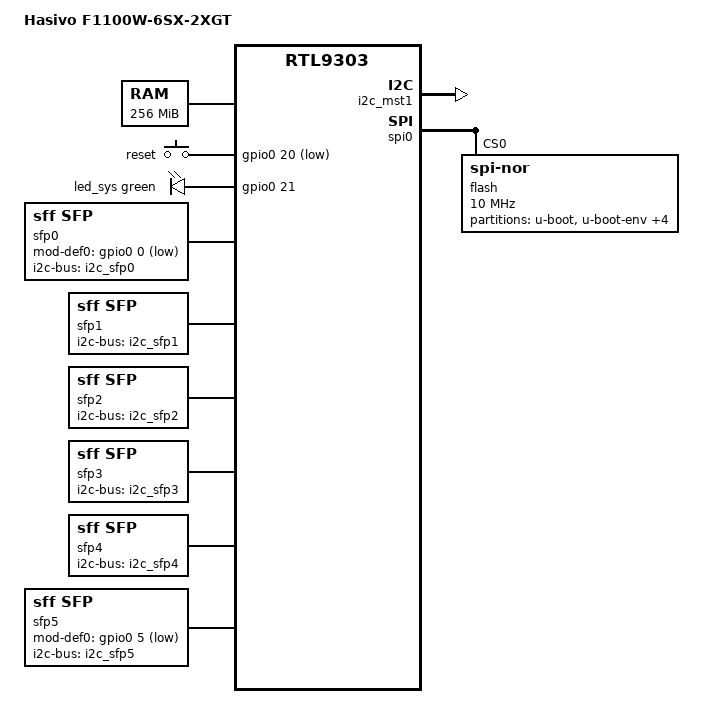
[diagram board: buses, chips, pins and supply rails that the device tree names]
// SPDX-License-Identifier: GPL-2.0-or-later
/dts-v1/;

#include "rtl930x.dtsi"

#include <dt-bindings/input/input.h>
#include <dt-bindings/gpio/gpio.h>
#include <dt-bindings/leds/common.h>

/ {
	compatible = "hasivo,f1100w-6sx-2xgt", "realtek,rtl9303-soc";
	model = "Hasivo F1100W-6SX-2XGT";

	memory@0 {
		reg = <0x00000000 0x10000000>;
	};

	aliases {
		led-boot = &led_sys;
		led-failsafe = &led_sys;
		led-running = &led_sys;
		led-upgrade = &led_sys;

		i2c0 = &i2c_sfp0;
		i2c1 = &i2c_sfp1;
		i2c2 = &i2c_sfp2;
		i2c3 = &i2c_sfp3;
		i2c4 = &i2c_sfp4;
		i2c5 = &i2c_sfp5;
	};

	chosen {
		stdout-path = "serial0:38400n8";
	};

	keys {
		compatible = "gpio-keys";

		button-reset {
			label = "reset";
			gpios = <&gpio0 20 GPIO_ACTIVE_LOW>;
			linux,code = <KEY_RESTART>;
		};
	};

	leds {
		compatible = "gpio-leds";

		/* GPIO confirmed; polarity provisionally follows the related 4SX board. */
		led_sys: led-0 {
			gpios = <&gpio0 21 GPIO_ACTIVE_HIGH>;
			color = <LED_COLOR_ID_GREEN>;
			function = LED_FUNCTION_STATUS;
		};
	};

	led_set {
		compatible = "realtek,rtl9300-leds";

		led_set0 = <
			(RTL93XX_LED_SET_NONE)
			(RTL93XX_LED_SET_10M | RTL93XX_LED_SET_100M | RTL93XX_LED_SET_1G |
			 RTL93XX_LED_SET_2P5G | RTL93XX_LED_SET_5G |
			 RTL93XX_LED_SET_LINK | RTL93XX_LED_SET_ACT)
			(RTL93XX_LED_SET_10G | RTL93XX_LED_SET_LINK | RTL93XX_LED_SET_ACT)
		>;
	};

	sfp0: sfp-p1 {
		compatible = "sff,sfp";
		i2c-bus = <&i2c_sfp0>;
		mod-def0-gpios = <&gpio0 0 GPIO_ACTIVE_LOW>;
		#thermal-sensor-cells = <0>;
	};

	sfp1: sfp-p2 {
		compatible = "sff,sfp";
		i2c-bus = <&i2c_sfp1>;
		#thermal-sensor-cells = <0>;
	};

	sfp2: sfp-p3 {
		compatible = "sff,sfp";
		i2c-bus = <&i2c_sfp2>;
		#thermal-sensor-cells = <0>;
	};

	sfp3: sfp-p4 {
		compatible = "sff,sfp";
		i2c-bus = <&i2c_sfp3>;
		#thermal-sensor-cells = <0>;
	};

	sfp4: sfp-p5 {
		compatible = "sff,sfp";
		i2c-bus = <&i2c_sfp4>;
		#thermal-sensor-cells = <0>;
	};

	sfp5: sfp-p6 {
		compatible = "sff,sfp";
		/* GPIO5 shares its pad with the auxiliary SPI interface. */
		pinctrl-names = "default";
		pinctrl-0 = <&pinmux_disable_spi0>;
		i2c-bus = <&i2c_sfp5>;
		mod-def0-gpios = <&gpio0 5 GPIO_ACTIVE_LOW>;
		#thermal-sensor-cells = <0>;
	};
};

&i2c_mst1 {
	status = "okay";

	i2c_sfp0: i2c@0 { reg = <0>; };
	i2c_sfp1: i2c@1 { reg = <1>; };
	i2c_sfp2: i2c@2 { reg = <2>; };
	i2c_sfp3: i2c@3 { reg = <3>; };
	i2c_sfp4: i2c@4 { reg = <4>; };
	i2c_sfp5: i2c@5 { reg = <5>; };
};

&spi0 {
	status = "okay";

	flash@0 {
		compatible = "jedec,spi-nor";
		reg = <0>;
		spi-max-frequency = <10000000>;

		partitions {
			compatible = "fixed-partitions";
			#address-cells = <1>;
			#size-cells = <1>;

			/* stock is LOADER */
			partition@0 {
				label = "u-boot";
				reg = <0x0000000 0x00e0000>;
				read-only;
			};

			/* stock is BDINFO */
			partition@e0000 {
				label = "u-boot-env";
				reg = <0x00e0000 0x0010000>;
				read-only;
			};

			/* stock is SYSINFO */
			partition@f0000 {
				label = "u-boot-env2";
				reg = <0x00f0000 0x0010000>;
				read-only;
			};

			/* stock is CFG JFFS2 */
			partition@100000 {
				label = "jffs";
				reg = <0x0100000 0x0100000>;
				read-only;
			};

			/* stock is LOG JFFS2 */
			partition@200000 {
				label = "jffs2";
				reg = <0x0200000 0x0100000>;
				read-only;
			};

			/* Combine stock RUNTIME and RUNTIME2 for kernel, rootfs and overlay. */
			partition@300000 {
				compatible = "openwrt,uimage", "denx,uimage";
				label = "firmware";
				reg = <0x0300000 0x1d00000>;
			};
		};
	};
};

&mdio_bus0 {
	PHY_C45(26, 16)
};

&mdio_bus1 {
	PHY_C45(27, 0)
};

&switch0 {
	ethernet-ports {
		#address-cells = <1>;
		#size-cells = <0>;

		/* SFP+ ports, lan1-6; presence for ports 2-5 is polled over I2C. */
		SWITCH_PORT_SFP(0, 1, 2, 0, 0)
		SWITCH_PORT_SFP(8, 2, 3, 0, 1)
		SWITCH_PORT_SFP(16, 3, 4, 0, 2)
		SWITCH_PORT_SFP(20, 4, 5, 0, 3)

		SWITCH_PORT_SFP(24, 5, 6, 0, 4)
		SWITCH_PORT_SFP(25, 6, 7, 0, 5)

		/* RJ45 ports, lan7-8 */
		SWITCH_PORT_LED(26, 7, 8, 0, 0, usxgmii)
		SWITCH_PORT_LED(27, 8, 9, 0, 0, usxgmii)

		/* CPU port */
		port@28 {
			ethernet = <&ethernet0>;
			reg = <28>;
			phy-mode = "internal";

			fixed-link {
				speed = <1000>;
				full-duplex;
			};
		};
	};
};

&thermal_zones {
	sfp-thermal {
		polling-delay-passive = <10000>;
		polling-delay = <10000>;
		thermal-sensors = <&sfp0>, <&sfp1>, <&sfp2>, <&sfp3>, <&sfp4>, <&sfp5>;
		trips {
			sfp-crit {
				temperature = <110000>;
				hysteresis = <1000>;
				type = "critical";
			};
		};
	};
};
